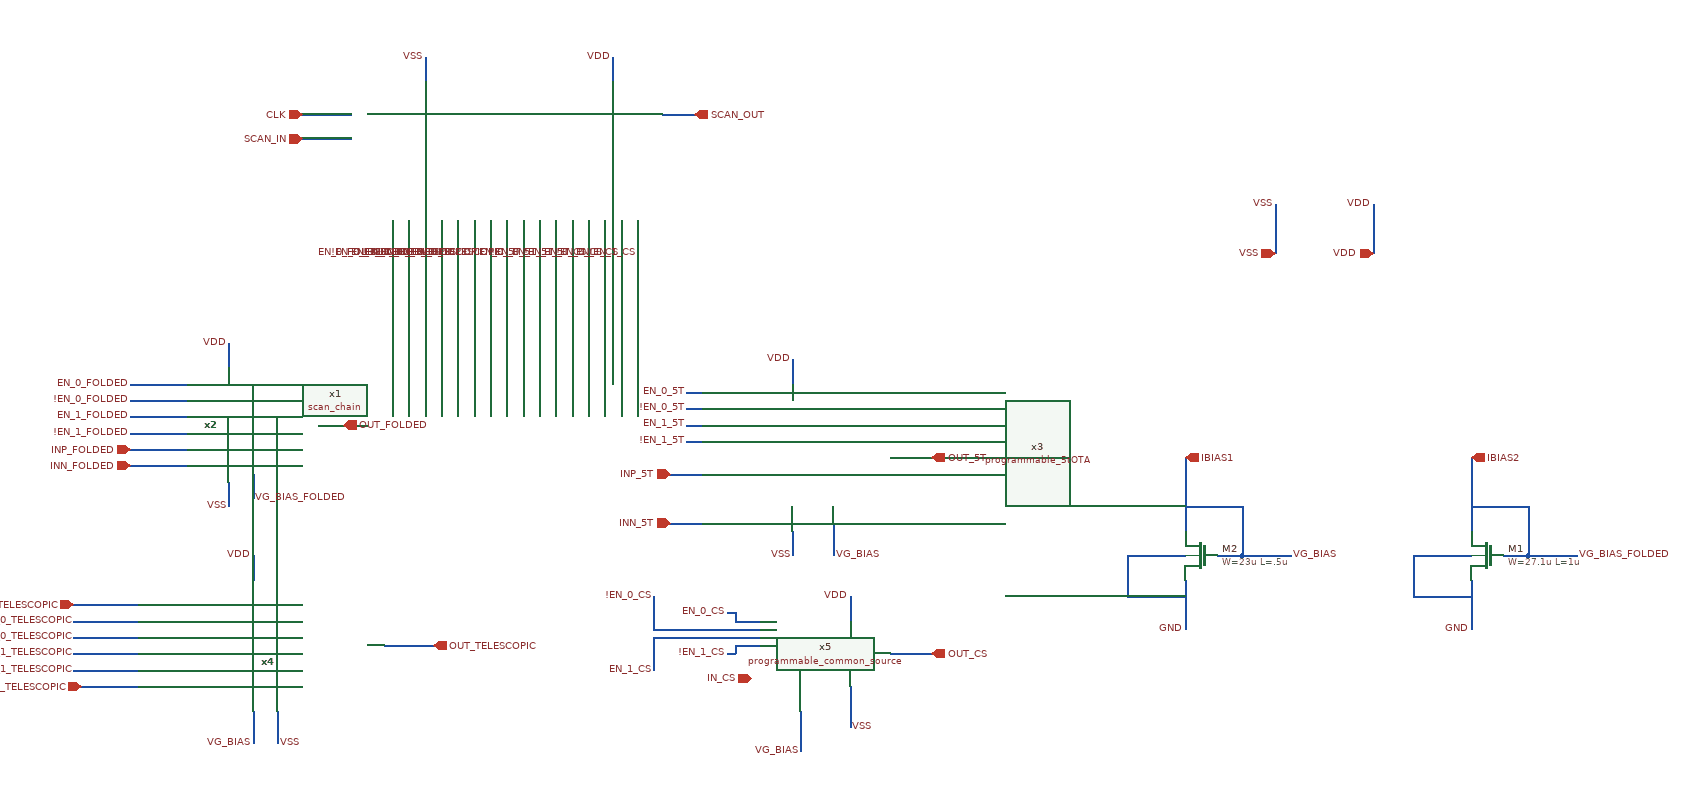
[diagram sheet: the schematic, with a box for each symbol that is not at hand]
v {xschem version=3.4.7 file_version=1.2}
G {}
K {}
V {}
S {}
E {}
P 4 1 1140 80 {}
N -220 150 -190 150 {lab=OUT_FOLDED}
N 480 190 530 190 {lab=OUT_5T}
N -140 420 -80 420 {lab=OUT_TELESCOPIC}
N 480 430 530 430 {lab=OUT_CS}
N 430 360 430 390 {lab=VDD}
N -300 310 -300 340 {lab=VDD}
N -330 50 -330 80 {lab=VDD}
N 360 70 360 100 {lab=VDD}
N 1070 -120 1070 -60 {lab=VDD}
N 950 -120 950 -60 {lab=VSS}
N -270 500 -270 540 {lab=VSS}
N 370 500 370 550 {lab=VG_BIAS}
N -330 220 -330 250 {lab=VSS}
N 360 280 360 310 {lab=VSS}
N 430 470 430 520 {lab=VSS}
N 1190 220 1190 260 {lab=VG_BIAS_FOLDED}
N 1190 260 1190 280 {lab=VG_BIAS_FOLDED}
N 1190 250 1260 250 {lab=VG_BIAS_FOLDED}
N 1260 250 1260 310 {lab=VG_BIAS_FOLDED}
N 1230 310 1260 310 {lab=VG_BIAS_FOLDED}
N 1190 340 1190 380 {lab=GND}
N 1120 310 1190 310 {lab=GND}
N 1120 310 1120 360 {lab=GND}
N 1120 360 1190 360 {lab=GND}
N 1190 380 1190 400 {lab=GND}
N 1190 190 1190 220 {lab=VG_BIAS_FOLDED}
N 1260 310 1320 310 {lab=VG_BIAS_FOLDED}
N 840 220 840 260 {lab=VG_BIAS}
N 840 260 840 280 {lab=VG_BIAS}
N 840 250 910 250 {lab=VG_BIAS}
N 910 250 910 310 {lab=VG_BIAS}
N 880 310 910 310 {lab=VG_BIAS}
N 840 340 840 380 {lab=GND}
N 770 310 840 310 {lab=GND}
N 770 310 770 360 {lab=GND}
N 770 360 840 360 {lab=GND}
N 840 380 840 400 {lab=GND}
N 840 190 840 220 {lab=VG_BIAS}
N 910 310 970 310 {lab=VG_BIAS}
N -300 210 -300 240 {lab=VG_BIAS_FOLDED}
N 410 270 410 310 {lab=VG_BIAS}
N -300 500 -300 540 {lab=VG_BIAS}
N -510 470 -440 470 {lab=INN_TELESCOPIC}
N -520 370 -440 370 {lab=INP_TELESCOPIC}
N -450 200 -380 200 {lab=INN_FOLDED}
N -450 180 -380 180 {lab=INP_FOLDED}
N 210 270 250 270 {lab=INN_5T}
N 210 210 250 210 {lab=INP_5T}
N -240 -230 -180 -230 {lab=CLK}
N -240 -200 -180 -200 {lab=SCAN_IN}
N 200 -230 240 -230 {lab=SCAN_OUT}
N -130 -100 -130 -60 {lab=EN_0_FOLDED}
N -110 -100 -110 -60 {lab=!EN_0_FOLDED}
N -90 -100 -90 -60 {lab=EN_1_FOLDED}
N -70 -100 -70 -60 {lab=!EN_1_FOLDED}
N -450 100 -380 100 {lab=EN_0_FOLDED}
N -450 120 -380 120 {lab=!EN_0_FOLDED}
N -450 140 -380 140 {lab=EN_1_FOLDED}
N -450 160 -380 160 {lab=!EN_1_FOLDED}
N -520 390 -440 390 {lab=EN_0_TELESCOPIC}
N -520 410 -440 410 {lab=!EN_0_TELESCOPIC}
N -520 430 -440 430 {lab=EN_1_TELESCOPIC}
N -520 450 -440 450 {lab=!EN_1_TELESCOPIC}
N 230 110 250 110 {lab=EN_0_5T}
N 230 130 250 130 {lab=!EN_0_5T}
N 230 150 250 150 {lab=EN_1_5T}
N 230 170 250 170 {lab=!EN_1_5T}
N 290 390 320 390 {lab=EN_0_CS}
N 290 400 320 400 {lab=!EN_0_CS}
N 290 410 320 410 {lab=EN_1_CS}
N 290 420 320 420 {lab=!EN_1_CS}
N 290 380 290 390 {lab=EN_0_CS}
N 290 420 290 430 {lab=!EN_1_CS}
N 280 430 290 430 {lab=!EN_1_CS}
N 190 410 290 410 {lab=EN_1_CS}
N 190 410 190 450 {lab=EN_1_CS}
N 190 400 290 400 {lab=!EN_0_CS}
N 190 360 190 400 {lab=!EN_0_CS}
N 280 380 290 380 {lab=EN_0_CS}
N -90 -300 -90 -270 {lab=VSS}
N 140 -300 140 -270 {lab=VDD}
N -50 -100 -50 -60 {lab=EN_0_TELESCOPIC}
N -30 -100 -30 -60 {lab=!EN_0_TELESCOPIC}
N -10 -100 -10 -60 {lab=EN_1_TELESCOPIC}
N 10 -100 10 -60 {lab=!EN_1_TELESCOPIC}
N 30 -100 30 -60 {lab=EN_0_5T}
N 50 -100 50 -60 {lab=!EN_0_5T}
N 70 -100 70 -60 {lab=EN_1_5T}
N 90 -100 90 -60 {lab=!EN_1_5T}
N 110 -100 110 -60 {lab=EN_0_CS}
N 130 -100 130 -60 {lab=!EN_0_CS}
N 150 -100 150 -60 {lab=EN_1_CS}
N 170 -100 170 -60 {lab=!EN_1_CS}
C {libs/core_digital/schem/scan_chain.sym} -80 -30 0 0 {name=x1}
C {libs/core_amps/ota_folded_cascode/prgrm_schem/programmable_folded_cascode.sym} -360 150 0 0 {name=x2}
C {libs/core_amps/ota_5t/schem/programmable_5tOTA.sym} 400 190 0 0 {name=x3}
C {libs/core_amps/ota_telescopic/programmable_ota_telescopic schematics/programmable_telescopic_cascode.sym} -290 440 0 0 {name=x4}
C {libs/core_amps/cs_stage/prgrm_schem/programmable_common_source.sym} 340 430 0 0 {name=x5}
C {iopin.sym} -190 150 2 1 {name=p35 lab=OUT_FOLDED}
C {iopin.sym} 530 190 2 1 {name=p1 lab=OUT_5T}
C {iopin.sym} -80 420 2 1 {name=p2 lab=OUT_TELESCOPIC}
C {iopin.sym} 530 430 2 1 {name=p3 lab=OUT_CS}
C {lab_pin.sym} 1070 -120 0 0 {name=p36 sig_type=std_logic lab=VDD}
C {lab_pin.sym} 950 -120 0 0 {name=p37 sig_type=std_logic lab=VSS}
C {iopin.sym} 950 -60 1 0 {name=p38 lab=VSS}
C {iopin.sym} 1070 -60 1 0 {name=p39 lab=VDD}
C {lab_pin.sym} -330 50 0 0 {name=p4 sig_type=std_logic lab=VDD}
C {lab_pin.sym} 360 70 0 0 {name=p5 sig_type=std_logic lab=VDD}
C {lab_pin.sym} -300 310 0 0 {name=p6 sig_type=std_logic lab=VDD}
C {lab_pin.sym} 430 360 0 0 {name=p7 sig_type=std_logic lab=VDD}
C {lab_pin.sym} -330 250 0 0 {name=p8 sig_type=std_logic lab=VSS}
C {lab_pin.sym} -270 540 0 1 {name=p9 sig_type=std_logic lab=VSS}
C {lab_pin.sym} 430 520 0 1 {name=p10 sig_type=std_logic lab=VSS}
C {lab_pin.sym} 360 310 0 0 {name=p11 sig_type=std_logic lab=VSS}
C {symbols/nfet_03v3.sym} 1210 310 0 1 {name=M1
L=1u
W=27.1u
nf=1
m=1
ad="'int((nf+1)/2) * W/nf * 0.18u'"
pd="'2*int((nf+1)/2) * (W/nf + 0.18u)'"
as="'int((nf+2)/2) * W/nf * 0.18u'"
ps="'2*int((nf+2)/2) * (W/nf + 0.18u)'"
nrd="'0.18u / W'" nrs="'0.18u / W'"
sa=0 sb=0 sd=0
model=nfet_03v3
spiceprefix=X
}
C {lab_pin.sym} 1320 310 0 1 {name=p12 sig_type=std_logic lab=VG_BIAS_FOLDED}
C {lab_pin.sym} 1190 400 0 0 {name=p16 sig_type=std_logic lab=GND}
C {symbols/nfet_03v3.sym} 860 310 0 1 {name=M2
L=.5u
W=23u
nf=1
m=1
ad="'int((nf+1)/2) * W/nf * 0.18u'"
pd="'2*int((nf+1)/2) * (W/nf + 0.18u)'"
as="'int((nf+2)/2) * W/nf * 0.18u'"
ps="'2*int((nf+2)/2) * (W/nf + 0.18u)'"
nrd="'0.18u / W'" nrs="'0.18u / W'"
sa=0 sb=0 sd=0
model=nfet_03v3
spiceprefix=X
}
C {lab_pin.sym} 970 310 0 1 {name=p13 sig_type=std_logic lab=VG_BIAS}
C {lab_pin.sym} 840 400 0 0 {name=p14 sig_type=std_logic lab=GND}
C {lab_pin.sym} -300 240 0 1 {name=p17 sig_type=std_logic lab=VG_BIAS_FOLDED}
C {lab_pin.sym} 410 310 0 1 {name=p18 sig_type=std_logic lab=VG_BIAS}
C {lab_pin.sym} 370 550 0 0 {name=p19 sig_type=std_logic lab=VG_BIAS}
C {lab_pin.sym} -300 540 0 0 {name=p20 sig_type=std_logic lab=VG_BIAS}
C {iopin.sym} -510 470 2 0 {name=p21 lab=INN_TELESCOPIC}
C {iopin.sym} -520 370 2 0 {name=p22 lab=INP_TELESCOPIC}
C {iopin.sym} -450 180 2 0 {name=p23 lab=INP_FOLDED}
C {iopin.sym} -450 200 2 0 {name=p24 lab=INN_FOLDED}
C {iopin.sym} 310 460 2 0 {name=p25 lab=IN_CS}
C {iopin.sym} 210 270 2 0 {name=p26 lab=INN_5T}
C {iopin.sym} 210 210 2 0 {name=p27 lab=INP_5T}
C {iopin.sym} -240 -230 2 0 {name=p28 lab=CLK}
C {iopin.sym} -240 -200 2 0 {name=p29 lab=SCAN_IN}
C {iopin.sym} 240 -230 2 1 {name=p30 lab=SCAN_OUT}
C {lab_pin.sym} -130 -60 3 0 {name=p15 sig_type=std_logic lab=EN_0_FOLDED}
C {lab_pin.sym} -450 100 2 1 {name=p31 sig_type=std_logic lab=EN_0_FOLDED}
C {lab_pin.sym} -110 -60 3 0 {name=p32 sig_type=std_logic lab=!EN_0_FOLDED}
C {lab_pin.sym} -450 120 2 1 {name=p33 sig_type=std_logic lab=!EN_0_FOLDED}
C {lab_pin.sym} -90 -60 3 0 {name=p34 sig_type=std_logic lab=EN_1_FOLDED}
C {lab_pin.sym} -450 140 0 0 {name=p40 sig_type=std_logic lab=EN_1_FOLDED}
C {lab_pin.sym} -70 -60 3 0 {name=p41 sig_type=std_logic lab=!EN_1_FOLDED}
C {lab_pin.sym} -450 160 0 0 {name=p42 sig_type=std_logic lab=!EN_1_FOLDED}
C {lab_pin.sym} -520 390 2 1 {name=p43 sig_type=std_logic lab=EN_0_TELESCOPIC}
C {lab_pin.sym} -520 410 2 1 {name=p44 sig_type=std_logic lab=!EN_0_TELESCOPIC}
C {lab_pin.sym} -520 430 0 0 {name=p45 sig_type=std_logic lab=EN_1_TELESCOPIC}
C {lab_pin.sym} -520 450 0 0 {name=p46 sig_type=std_logic lab=!EN_1_TELESCOPIC}
C {lab_pin.sym} 230 110 2 1 {name=p47 sig_type=std_logic lab=EN_0_5T}
C {lab_pin.sym} 230 130 2 1 {name=p48 sig_type=std_logic lab=!EN_0_5T}
C {lab_pin.sym} 230 150 0 0 {name=p49 sig_type=std_logic lab=EN_1_5T}
C {lab_pin.sym} 230 170 0 0 {name=p50 sig_type=std_logic lab=!EN_1_5T}
C {lab_pin.sym} 280 380 2 1 {name=p51 sig_type=std_logic lab=EN_0_CS}
C {lab_pin.sym} 280 430 0 0 {name=p52 sig_type=std_logic lab=!EN_1_CS}
C {lab_pin.sym} 190 450 0 0 {name=p53 sig_type=std_logic lab=EN_1_CS}
C {lab_pin.sym} 190 360 2 1 {name=p54 sig_type=std_logic lab=!EN_0_CS}
C {lab_pin.sym} -90 -300 0 0 {name=p55 sig_type=std_logic lab=VSS}
C {lab_pin.sym} 140 -300 0 0 {name=p56 sig_type=std_logic lab=VDD}
C {lab_pin.sym} -50 -60 3 0 {name=p57 sig_type=std_logic lab=EN_0_TELESCOPIC}
C {lab_pin.sym} -30 -60 3 0 {name=p58 sig_type=std_logic lab=!EN_0_TELESCOPIC}
C {lab_pin.sym} -10 -60 3 0 {name=p59 sig_type=std_logic lab=EN_1_TELESCOPIC}
C {lab_pin.sym} 10 -60 3 0 {name=p60 sig_type=std_logic lab=!EN_1_TELESCOPIC}
C {lab_pin.sym} 30 -60 3 0 {name=p61 sig_type=std_logic lab=EN_0_5T}
C {lab_pin.sym} 50 -60 3 0 {name=p62 sig_type=std_logic lab=!EN_0_5T}
C {lab_pin.sym} 70 -60 3 0 {name=p63 sig_type=std_logic lab=EN_1_5T}
C {lab_pin.sym} 90 -60 3 0 {name=p64 sig_type=std_logic lab=!EN_1_5T}
C {lab_pin.sym} 110 -60 3 0 {name=p65 sig_type=std_logic lab=EN_0_CS}
C {lab_pin.sym} 130 -60 3 0 {name=p66 sig_type=std_logic lab=!EN_0_CS}
C {lab_pin.sym} 150 -60 3 0 {name=p67 sig_type=std_logic lab=EN_1_CS}
C {lab_pin.sym} 170 -60 3 0 {name=p68 sig_type=std_logic lab=!EN_1_CS}
C {iopin.sym} 840 190 1 1 {name=p69 lab=IBIAS1}
C {iopin.sym} 1190 190 1 1 {name=p70 lab=IBIAS2}
